# Generated by FakeRAM 2.0 (routing-friendly)
VERSION 5.7 ;
BUSBITCHARS "[]" ;
PROPERTYDEFINITIONS
  MACRO width INTEGER ;
  MACRO depth INTEGER ;
  MACRO banks INTEGER ;
END PROPERTYDEFINITIONS
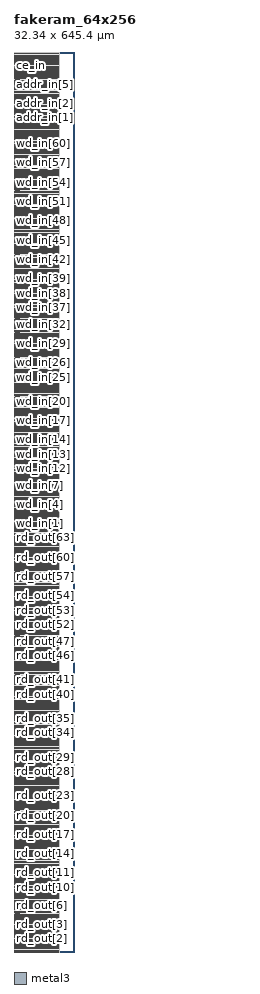
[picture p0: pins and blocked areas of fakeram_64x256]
MACRO fakeram_64x256
  PROPERTY width 64 ;
  PROPERTY depth 256 ;
  PROPERTY banks 1 ;
  FOREIGN fakeram_64x256 0 0 ;
  SYMMETRY X Y R90 ;
  SIZE 32.340 BY 645.400 ;
  CLASS BLOCK ;
  PIN rd_out[0]
    DIRECTION OUTPUT ;
    USE SIGNAL ;
    PORT
      LAYER metal3 ;
      RECT 1.000 0.140 3.000 0.210 ;
    END
    PORT
      LAYER metal3 ;
      RECT 1.000 0.105 4.000 0.245 ;
    END
  END rd_out[0]
  PIN rd_out[1]
    DIRECTION OUTPUT ;
    USE SIGNAL ;
    PORT
      LAYER metal3 ;
      RECT 1.000 4.760 3.000 4.830 ;
    END
    PORT
      LAYER metal3 ;
      RECT 1.000 4.725 4.000 4.865 ;
    END
  END rd_out[1]
  PIN rd_out[2]
    DIRECTION OUTPUT ;
    USE SIGNAL ;
    PORT
      LAYER metal3 ;
      RECT 1.000 9.380 3.000 9.450 ;
    END
    PORT
      LAYER metal3 ;
      RECT 1.000 9.345 4.000 9.485 ;
    END
  END rd_out[2]
  PIN rd_out[3]
    DIRECTION OUTPUT ;
    USE SIGNAL ;
    PORT
      LAYER metal3 ;
      RECT 1.000 14.000 3.000 14.070 ;
    END
    PORT
      LAYER metal3 ;
      RECT 1.000 13.965 4.000 14.105 ;
    END
  END rd_out[3]
  PIN rd_out[4]
    DIRECTION OUTPUT ;
    USE SIGNAL ;
    PORT
      LAYER metal3 ;
      RECT 1.000 18.620 3.000 18.690 ;
    END
    PORT
      LAYER metal3 ;
      RECT 1.000 18.585 4.000 18.725 ;
    END
  END rd_out[4]
  PIN rd_out[5]
    DIRECTION OUTPUT ;
    USE SIGNAL ;
    PORT
      LAYER metal3 ;
      RECT 1.000 23.240 3.000 23.310 ;
    END
    PORT
      LAYER metal3 ;
      RECT 1.000 23.205 4.000 23.345 ;
    END
  END rd_out[5]
  PIN rd_out[6]
    DIRECTION OUTPUT ;
    USE SIGNAL ;
    PORT
      LAYER metal3 ;
      RECT 1.000 27.860 3.000 27.930 ;
    END
    PORT
      LAYER metal3 ;
      RECT 1.000 27.825 4.000 27.965 ;
    END
  END rd_out[6]
  PIN rd_out[7]
    DIRECTION OUTPUT ;
    USE SIGNAL ;
    PORT
      LAYER metal3 ;
      RECT 1.000 32.480 3.000 32.550 ;
    END
    PORT
      LAYER metal3 ;
      RECT 1.000 32.445 4.000 32.585 ;
    END
  END rd_out[7]
  PIN rd_out[8]
    DIRECTION OUTPUT ;
    USE SIGNAL ;
    PORT
      LAYER metal3 ;
      RECT 1.000 37.100 3.000 37.170 ;
    END
    PORT
      LAYER metal3 ;
      RECT 1.000 37.065 4.000 37.205 ;
    END
  END rd_out[8]
  PIN rd_out[9]
    DIRECTION OUTPUT ;
    USE SIGNAL ;
    PORT
      LAYER metal3 ;
      RECT 1.000 41.720 3.000 41.790 ;
    END
    PORT
      LAYER metal3 ;
      RECT 1.000 41.685 4.000 41.825 ;
    END
  END rd_out[9]
  PIN rd_out[10]
    DIRECTION OUTPUT ;
    USE SIGNAL ;
    PORT
      LAYER metal3 ;
      RECT 1.000 46.340 3.000 46.410 ;
    END
    PORT
      LAYER metal3 ;
      RECT 1.000 46.305 4.000 46.445 ;
    END
  END rd_out[10]
  PIN rd_out[11]
    DIRECTION OUTPUT ;
    USE SIGNAL ;
    PORT
      LAYER metal3 ;
      RECT 1.000 50.960 3.000 51.030 ;
    END
    PORT
      LAYER metal3 ;
      RECT 1.000 50.925 4.000 51.065 ;
    END
  END rd_out[11]
  PIN rd_out[12]
    DIRECTION OUTPUT ;
    USE SIGNAL ;
    PORT
      LAYER metal3 ;
      RECT 1.000 55.580 3.000 55.650 ;
    END
    PORT
      LAYER metal3 ;
      RECT 1.000 55.545 4.000 55.685 ;
    END
  END rd_out[12]
  PIN rd_out[13]
    DIRECTION OUTPUT ;
    USE SIGNAL ;
    PORT
      LAYER metal3 ;
      RECT 1.000 60.200 3.000 60.270 ;
    END
    PORT
      LAYER metal3 ;
      RECT 1.000 60.165 4.000 60.305 ;
    END
  END rd_out[13]
  PIN rd_out[14]
    DIRECTION OUTPUT ;
    USE SIGNAL ;
    PORT
      LAYER metal3 ;
      RECT 1.000 64.820 3.000 64.890 ;
    END
    PORT
      LAYER metal3 ;
      RECT 1.000 64.785 4.000 64.925 ;
    END
  END rd_out[14]
  PIN rd_out[15]
    DIRECTION OUTPUT ;
    USE SIGNAL ;
    PORT
      LAYER metal3 ;
      RECT 1.000 69.440 3.000 69.510 ;
    END
    PORT
      LAYER metal3 ;
      RECT 1.000 69.405 4.000 69.545 ;
    END
  END rd_out[15]
  PIN rd_out[16]
    DIRECTION OUTPUT ;
    USE SIGNAL ;
    PORT
      LAYER metal3 ;
      RECT 1.000 74.060 3.000 74.130 ;
    END
    PORT
      LAYER metal3 ;
      RECT 1.000 74.025 4.000 74.165 ;
    END
  END rd_out[16]
  PIN rd_out[17]
    DIRECTION OUTPUT ;
    USE SIGNAL ;
    PORT
      LAYER metal3 ;
      RECT 1.000 78.680 3.000 78.750 ;
    END
    PORT
      LAYER metal3 ;
      RECT 1.000 78.645 4.000 78.785 ;
    END
  END rd_out[17]
  PIN rd_out[18]
    DIRECTION OUTPUT ;
    USE SIGNAL ;
    PORT
      LAYER metal3 ;
      RECT 1.000 83.300 3.000 83.370 ;
    END
    PORT
      LAYER metal3 ;
      RECT 1.000 83.265 4.000 83.405 ;
    END
  END rd_out[18]
  PIN rd_out[19]
    DIRECTION OUTPUT ;
    USE SIGNAL ;
    PORT
      LAYER metal3 ;
      RECT 1.000 87.920 3.000 87.990 ;
    END
    PORT
      LAYER metal3 ;
      RECT 1.000 87.885 4.000 88.025 ;
    END
  END rd_out[19]
  PIN rd_out[20]
    DIRECTION OUTPUT ;
    USE SIGNAL ;
    PORT
      LAYER metal3 ;
      RECT 1.000 92.540 3.000 92.610 ;
    END
    PORT
      LAYER metal3 ;
      RECT 1.000 92.505 4.000 92.645 ;
    END
  END rd_out[20]
  PIN rd_out[21]
    DIRECTION OUTPUT ;
    USE SIGNAL ;
    PORT
      LAYER metal3 ;
      RECT 1.000 97.160 3.000 97.230 ;
    END
    PORT
      LAYER metal3 ;
      RECT 1.000 97.125 4.000 97.265 ;
    END
  END rd_out[21]
  PIN rd_out[22]
    DIRECTION OUTPUT ;
    USE SIGNAL ;
    PORT
      LAYER metal3 ;
      RECT 1.000 101.780 3.000 101.850 ;
    END
    PORT
      LAYER metal3 ;
      RECT 1.000 101.745 4.000 101.885 ;
    END
  END rd_out[22]
  PIN rd_out[23]
    DIRECTION OUTPUT ;
    USE SIGNAL ;
    PORT
      LAYER metal3 ;
      RECT 1.000 106.400 3.000 106.470 ;
    END
    PORT
      LAYER metal3 ;
      RECT 1.000 106.365 4.000 106.505 ;
    END
  END rd_out[23]
  PIN rd_out[24]
    DIRECTION OUTPUT ;
    USE SIGNAL ;
    PORT
      LAYER metal3 ;
      RECT 1.000 111.020 3.000 111.090 ;
    END
    PORT
      LAYER metal3 ;
      RECT 1.000 110.985 4.000 111.125 ;
    END
  END rd_out[24]
  PIN rd_out[25]
    DIRECTION OUTPUT ;
    USE SIGNAL ;
    PORT
      LAYER metal3 ;
      RECT 1.000 115.640 3.000 115.710 ;
    END
    PORT
      LAYER metal3 ;
      RECT 1.000 115.605 4.000 115.745 ;
    END
  END rd_out[25]
  PIN rd_out[26]
    DIRECTION OUTPUT ;
    USE SIGNAL ;
    PORT
      LAYER metal3 ;
      RECT 1.000 120.260 3.000 120.330 ;
    END
    PORT
      LAYER metal3 ;
      RECT 1.000 120.225 4.000 120.365 ;
    END
  END rd_out[26]
  PIN rd_out[27]
    DIRECTION OUTPUT ;
    USE SIGNAL ;
    PORT
      LAYER metal3 ;
      RECT 1.000 124.880 3.000 124.950 ;
    END
    PORT
      LAYER metal3 ;
      RECT 1.000 124.845 4.000 124.985 ;
    END
  END rd_out[27]
  PIN rd_out[28]
    DIRECTION OUTPUT ;
    USE SIGNAL ;
    PORT
      LAYER metal3 ;
      RECT 1.000 129.500 3.000 129.570 ;
    END
    PORT
      LAYER metal3 ;
      RECT 1.000 129.465 4.000 129.605 ;
    END
  END rd_out[28]
  PIN rd_out[29]
    DIRECTION OUTPUT ;
    USE SIGNAL ;
    PORT
      LAYER metal3 ;
      RECT 1.000 134.120 3.000 134.190 ;
    END
    PORT
      LAYER metal3 ;
      RECT 1.000 134.085 4.000 134.225 ;
    END
  END rd_out[29]
  PIN rd_out[30]
    DIRECTION OUTPUT ;
    USE SIGNAL ;
    PORT
      LAYER metal3 ;
      RECT 1.000 138.740 3.000 138.810 ;
    END
    PORT
      LAYER metal3 ;
      RECT 1.000 138.705 4.000 138.845 ;
    END
  END rd_out[30]
  PIN rd_out[31]
    DIRECTION OUTPUT ;
    USE SIGNAL ;
    PORT
      LAYER metal3 ;
      RECT 1.000 143.360 3.000 143.430 ;
    END
    PORT
      LAYER metal3 ;
      RECT 1.000 143.325 4.000 143.465 ;
    END
  END rd_out[31]
  PIN rd_out[32]
    DIRECTION OUTPUT ;
    USE SIGNAL ;
    PORT
      LAYER metal3 ;
      RECT 1.000 147.980 3.000 148.050 ;
    END
    PORT
      LAYER metal3 ;
      RECT 1.000 147.945 4.000 148.085 ;
    END
  END rd_out[32]
  PIN rd_out[33]
    DIRECTION OUTPUT ;
    USE SIGNAL ;
    PORT
      LAYER metal3 ;
      RECT 1.000 152.600 3.000 152.670 ;
    END
    PORT
      LAYER metal3 ;
      RECT 1.000 152.565 4.000 152.705 ;
    END
  END rd_out[33]
  PIN rd_out[34]
    DIRECTION OUTPUT ;
    USE SIGNAL ;
    PORT
      LAYER metal3 ;
      RECT 1.000 157.220 3.000 157.290 ;
    END
    PORT
      LAYER metal3 ;
      RECT 1.000 157.185 4.000 157.325 ;
    END
  END rd_out[34]
  PIN rd_out[35]
    DIRECTION OUTPUT ;
    USE SIGNAL ;
    PORT
      LAYER metal3 ;
      RECT 1.000 161.840 3.000 161.910 ;
    END
    PORT
      LAYER metal3 ;
      RECT 1.000 161.805 4.000 161.945 ;
    END
  END rd_out[35]
  PIN rd_out[36]
    DIRECTION OUTPUT ;
    USE SIGNAL ;
    PORT
      LAYER metal3 ;
      RECT 1.000 166.460 3.000 166.530 ;
    END
    PORT
      LAYER metal3 ;
      RECT 1.000 166.425 4.000 166.565 ;
    END
  END rd_out[36]
  PIN rd_out[37]
    DIRECTION OUTPUT ;
    USE SIGNAL ;
    PORT
      LAYER metal3 ;
      RECT 1.000 171.080 3.000 171.150 ;
    END
    PORT
      LAYER metal3 ;
      RECT 1.000 171.045 4.000 171.185 ;
    END
  END rd_out[37]
  PIN rd_out[38]
    DIRECTION OUTPUT ;
    USE SIGNAL ;
    PORT
      LAYER metal3 ;
      RECT 1.000 175.700 3.000 175.770 ;
    END
    PORT
      LAYER metal3 ;
      RECT 1.000 175.665 4.000 175.805 ;
    END
  END rd_out[38]
  PIN rd_out[39]
    DIRECTION OUTPUT ;
    USE SIGNAL ;
    PORT
      LAYER metal3 ;
      RECT 1.000 180.320 3.000 180.390 ;
    END
    PORT
      LAYER metal3 ;
      RECT 1.000 180.285 4.000 180.425 ;
    END
  END rd_out[39]
  PIN rd_out[40]
    DIRECTION OUTPUT ;
    USE SIGNAL ;
    PORT
      LAYER metal3 ;
      RECT 1.000 184.940 3.000 185.010 ;
    END
    PORT
      LAYER metal3 ;
      RECT 1.000 184.905 4.000 185.045 ;
    END
  END rd_out[40]
  PIN rd_out[41]
    DIRECTION OUTPUT ;
    USE SIGNAL ;
    PORT
      LAYER metal3 ;
      RECT 1.000 189.560 3.000 189.630 ;
    END
    PORT
      LAYER metal3 ;
      RECT 1.000 189.525 4.000 189.665 ;
    END
  END rd_out[41]
  PIN rd_out[42]
    DIRECTION OUTPUT ;
    USE SIGNAL ;
    PORT
      LAYER metal3 ;
      RECT 1.000 194.180 3.000 194.250 ;
    END
    PORT
      LAYER metal3 ;
      RECT 1.000 194.145 4.000 194.285 ;
    END
  END rd_out[42]
  PIN rd_out[43]
    DIRECTION OUTPUT ;
    USE SIGNAL ;
    PORT
      LAYER metal3 ;
      RECT 1.000 198.800 3.000 198.870 ;
    END
    PORT
      LAYER metal3 ;
      RECT 1.000 198.765 4.000 198.905 ;
    END
  END rd_out[43]
  PIN rd_out[44]
    DIRECTION OUTPUT ;
    USE SIGNAL ;
    PORT
      LAYER metal3 ;
      RECT 1.000 203.420 3.000 203.490 ;
    END
    PORT
      LAYER metal3 ;
      RECT 1.000 203.385 4.000 203.525 ;
    END
  END rd_out[44]
  PIN rd_out[45]
    DIRECTION OUTPUT ;
    USE SIGNAL ;
    PORT
      LAYER metal3 ;
      RECT 1.000 208.040 3.000 208.110 ;
    END
    PORT
      LAYER metal3 ;
      RECT 1.000 208.005 4.000 208.145 ;
    END
  END rd_out[45]
  PIN rd_out[46]
    DIRECTION OUTPUT ;
    USE SIGNAL ;
    PORT
      LAYER metal3 ;
      RECT 1.000 212.660 3.000 212.730 ;
    END
    PORT
      LAYER metal3 ;
      RECT 1.000 212.625 4.000 212.765 ;
    END
  END rd_out[46]
  PIN rd_out[47]
    DIRECTION OUTPUT ;
    USE SIGNAL ;
    PORT
      LAYER metal3 ;
      RECT 1.000 217.280 3.000 217.350 ;
    END
    PORT
      LAYER metal3 ;
      RECT 1.000 217.245 4.000 217.385 ;
    END
  END rd_out[47]
  PIN rd_out[48]
    DIRECTION OUTPUT ;
    USE SIGNAL ;
    PORT
      LAYER metal3 ;
      RECT 1.000 221.900 3.000 221.970 ;
    END
    PORT
      LAYER metal3 ;
      RECT 1.000 221.865 4.000 222.005 ;
    END
  END rd_out[48]
  PIN rd_out[49]
    DIRECTION OUTPUT ;
    USE SIGNAL ;
    PORT
      LAYER metal3 ;
      RECT 1.000 226.520 3.000 226.590 ;
    END
    PORT
      LAYER metal3 ;
      RECT 1.000 226.485 4.000 226.625 ;
    END
  END rd_out[49]
  PIN rd_out[50]
    DIRECTION OUTPUT ;
    USE SIGNAL ;
    PORT
      LAYER metal3 ;
      RECT 1.000 231.140 3.000 231.210 ;
    END
    PORT
      LAYER metal3 ;
      RECT 1.000 231.105 4.000 231.245 ;
    END
  END rd_out[50]
  PIN rd_out[51]
    DIRECTION OUTPUT ;
    USE SIGNAL ;
    PORT
      LAYER metal3 ;
      RECT 1.000 235.760 3.000 235.830 ;
    END
    PORT
      LAYER metal3 ;
      RECT 1.000 235.725 4.000 235.865 ;
    END
  END rd_out[51]
  PIN rd_out[52]
    DIRECTION OUTPUT ;
    USE SIGNAL ;
    PORT
      LAYER metal3 ;
      RECT 1.000 240.380 3.000 240.450 ;
    END
    PORT
      LAYER metal3 ;
      RECT 1.000 240.345 4.000 240.485 ;
    END
  END rd_out[52]
  PIN rd_out[53]
    DIRECTION OUTPUT ;
    USE SIGNAL ;
    PORT
      LAYER metal3 ;
      RECT 1.000 245.000 3.000 245.070 ;
    END
    PORT
      LAYER metal3 ;
      RECT 1.000 244.965 4.000 245.105 ;
    END
  END rd_out[53]
  PIN rd_out[54]
    DIRECTION OUTPUT ;
    USE SIGNAL ;
    PORT
      LAYER metal3 ;
      RECT 1.000 249.620 3.000 249.690 ;
    END
    PORT
      LAYER metal3 ;
      RECT 1.000 249.585 4.000 249.725 ;
    END
  END rd_out[54]
  PIN rd_out[55]
    DIRECTION OUTPUT ;
    USE SIGNAL ;
    PORT
      LAYER metal3 ;
      RECT 1.000 254.240 3.000 254.310 ;
    END
    PORT
      LAYER metal3 ;
      RECT 1.000 254.205 4.000 254.345 ;
    END
  END rd_out[55]
  PIN rd_out[56]
    DIRECTION OUTPUT ;
    USE SIGNAL ;
    PORT
      LAYER metal3 ;
      RECT 1.000 258.860 3.000 258.930 ;
    END
    PORT
      LAYER metal3 ;
      RECT 1.000 258.825 4.000 258.965 ;
    END
  END rd_out[56]
  PIN rd_out[57]
    DIRECTION OUTPUT ;
    USE SIGNAL ;
    PORT
      LAYER metal3 ;
      RECT 1.000 263.480 3.000 263.550 ;
    END
    PORT
      LAYER metal3 ;
      RECT 1.000 263.445 4.000 263.585 ;
    END
  END rd_out[57]
  PIN rd_out[58]
    DIRECTION OUTPUT ;
    USE SIGNAL ;
    PORT
      LAYER metal3 ;
      RECT 1.000 268.100 3.000 268.170 ;
    END
    PORT
      LAYER metal3 ;
      RECT 1.000 268.065 4.000 268.205 ;
    END
  END rd_out[58]
  PIN rd_out[59]
    DIRECTION OUTPUT ;
    USE SIGNAL ;
    PORT
      LAYER metal3 ;
      RECT 1.000 272.720 3.000 272.790 ;
    END
    PORT
      LAYER metal3 ;
      RECT 1.000 272.685 4.000 272.825 ;
    END
  END rd_out[59]
  PIN rd_out[60]
    DIRECTION OUTPUT ;
    USE SIGNAL ;
    PORT
      LAYER metal3 ;
      RECT 1.000 277.340 3.000 277.410 ;
    END
    PORT
      LAYER metal3 ;
      RECT 1.000 277.305 4.000 277.445 ;
    END
  END rd_out[60]
  PIN rd_out[61]
    DIRECTION OUTPUT ;
    USE SIGNAL ;
    PORT
      LAYER metal3 ;
      RECT 1.000 281.960 3.000 282.030 ;
    END
    PORT
      LAYER metal3 ;
      RECT 1.000 281.925 4.000 282.065 ;
    END
  END rd_out[61]
  PIN rd_out[62]
    DIRECTION OUTPUT ;
    USE SIGNAL ;
    PORT
      LAYER metal3 ;
      RECT 1.000 286.580 3.000 286.650 ;
    END
    PORT
      LAYER metal3 ;
      RECT 1.000 286.545 4.000 286.685 ;
    END
  END rd_out[62]
  PIN rd_out[63]
    DIRECTION OUTPUT ;
    USE SIGNAL ;
    PORT
      LAYER metal3 ;
      RECT 1.000 291.200 3.000 291.270 ;
    END
    PORT
      LAYER metal3 ;
      RECT 1.000 291.165 4.000 291.305 ;
    END
  END rd_out[63]
  PIN wd_in[0]
    DIRECTION INPUT ;
    USE SIGNAL ;
    PORT
      LAYER metal3 ;
      RECT 1.000 296.800 3.000 296.870 ;
    END
    PORT
      LAYER metal3 ;
      RECT 1.000 296.765 4.000 296.905 ;
    END
  END wd_in[0]
  PIN wd_in[1]
    DIRECTION INPUT ;
    USE SIGNAL ;
    PORT
      LAYER metal3 ;
      RECT 1.000 301.420 3.000 301.490 ;
    END
    PORT
      LAYER metal3 ;
      RECT 1.000 301.385 4.000 301.525 ;
    END
  END wd_in[1]
  PIN wd_in[2]
    DIRECTION INPUT ;
    USE SIGNAL ;
    PORT
      LAYER metal3 ;
      RECT 1.000 306.040 3.000 306.110 ;
    END
    PORT
      LAYER metal3 ;
      RECT 1.000 306.005 4.000 306.145 ;
    END
  END wd_in[2]
  PIN wd_in[3]
    DIRECTION INPUT ;
    USE SIGNAL ;
    PORT
      LAYER metal3 ;
      RECT 1.000 310.660 3.000 310.730 ;
    END
    PORT
      LAYER metal3 ;
      RECT 1.000 310.625 4.000 310.765 ;
    END
  END wd_in[3]
  PIN wd_in[4]
    DIRECTION INPUT ;
    USE SIGNAL ;
    PORT
      LAYER metal3 ;
      RECT 1.000 315.280 3.000 315.350 ;
    END
    PORT
      LAYER metal3 ;
      RECT 1.000 315.245 4.000 315.385 ;
    END
  END wd_in[4]
  PIN wd_in[5]
    DIRECTION INPUT ;
    USE SIGNAL ;
    PORT
      LAYER metal3 ;
      RECT 1.000 319.900 3.000 319.970 ;
    END
    PORT
      LAYER metal3 ;
      RECT 1.000 319.865 4.000 320.005 ;
    END
  END wd_in[5]
  PIN wd_in[6]
    DIRECTION INPUT ;
    USE SIGNAL ;
    PORT
      LAYER metal3 ;
      RECT 1.000 324.520 3.000 324.590 ;
    END
    PORT
      LAYER metal3 ;
      RECT 1.000 324.485 4.000 324.625 ;
    END
  END wd_in[6]
  PIN wd_in[7]
    DIRECTION INPUT ;
    USE SIGNAL ;
    PORT
      LAYER metal3 ;
      RECT 1.000 329.140 3.000 329.210 ;
    END
    PORT
      LAYER metal3 ;
      RECT 1.000 329.105 4.000 329.245 ;
    END
  END wd_in[7]
  PIN wd_in[8]
    DIRECTION INPUT ;
    USE SIGNAL ;
    PORT
      LAYER metal3 ;
      RECT 1.000 333.760 3.000 333.830 ;
    END
    PORT
      LAYER metal3 ;
      RECT 1.000 333.725 4.000 333.865 ;
    END
  END wd_in[8]
  PIN wd_in[9]
    DIRECTION INPUT ;
    USE SIGNAL ;
    PORT
      LAYER metal3 ;
      RECT 1.000 338.380 3.000 338.450 ;
    END
    PORT
      LAYER metal3 ;
      RECT 1.000 338.345 4.000 338.485 ;
    END
  END wd_in[9]
  PIN wd_in[10]
    DIRECTION INPUT ;
    USE SIGNAL ;
    PORT
      LAYER metal3 ;
      RECT 1.000 343.000 3.000 343.070 ;
    END
    PORT
      LAYER metal3 ;
      RECT 1.000 342.965 4.000 343.105 ;
    END
  END wd_in[10]
  PIN wd_in[11]
    DIRECTION INPUT ;
    USE SIGNAL ;
    PORT
      LAYER metal3 ;
      RECT 1.000 347.620 3.000 347.690 ;
    END
    PORT
      LAYER metal3 ;
      RECT 1.000 347.585 4.000 347.725 ;
    END
  END wd_in[11]
  PIN wd_in[12]
    DIRECTION INPUT ;
    USE SIGNAL ;
    PORT
      LAYER metal3 ;
      RECT 1.000 352.240 3.000 352.310 ;
    END
    PORT
      LAYER metal3 ;
      RECT 1.000 352.205 4.000 352.345 ;
    END
  END wd_in[12]
  PIN wd_in[13]
    DIRECTION INPUT ;
    USE SIGNAL ;
    PORT
      LAYER metal3 ;
      RECT 1.000 356.860 3.000 356.930 ;
    END
    PORT
      LAYER metal3 ;
      RECT 1.000 356.825 4.000 356.965 ;
    END
  END wd_in[13]
  PIN wd_in[14]
    DIRECTION INPUT ;
    USE SIGNAL ;
    PORT
      LAYER metal3 ;
      RECT 1.000 361.480 3.000 361.550 ;
    END
    PORT
      LAYER metal3 ;
      RECT 1.000 361.445 4.000 361.585 ;
    END
  END wd_in[14]
  PIN wd_in[15]
    DIRECTION INPUT ;
    USE SIGNAL ;
    PORT
      LAYER metal3 ;
      RECT 1.000 366.100 3.000 366.170 ;
    END
    PORT
      LAYER metal3 ;
      RECT 1.000 366.065 4.000 366.205 ;
    END
  END wd_in[15]
  PIN wd_in[16]
    DIRECTION INPUT ;
    USE SIGNAL ;
    PORT
      LAYER metal3 ;
      RECT 1.000 370.720 3.000 370.790 ;
    END
    PORT
      LAYER metal3 ;
      RECT 1.000 370.685 4.000 370.825 ;
    END
  END wd_in[16]
  PIN wd_in[17]
    DIRECTION INPUT ;
    USE SIGNAL ;
    PORT
      LAYER metal3 ;
      RECT 1.000 375.340 3.000 375.410 ;
    END
    PORT
      LAYER metal3 ;
      RECT 1.000 375.305 4.000 375.445 ;
    END
  END wd_in[17]
  PIN wd_in[18]
    DIRECTION INPUT ;
    USE SIGNAL ;
    PORT
      LAYER metal3 ;
      RECT 1.000 379.960 3.000 380.030 ;
    END
    PORT
      LAYER metal3 ;
      RECT 1.000 379.925 4.000 380.065 ;
    END
  END wd_in[18]
  PIN wd_in[19]
    DIRECTION INPUT ;
    USE SIGNAL ;
    PORT
      LAYER metal3 ;
      RECT 1.000 384.580 3.000 384.650 ;
    END
    PORT
      LAYER metal3 ;
      RECT 1.000 384.545 4.000 384.685 ;
    END
  END wd_in[19]
  PIN wd_in[20]
    DIRECTION INPUT ;
    USE SIGNAL ;
    PORT
      LAYER metal3 ;
      RECT 1.000 389.200 3.000 389.270 ;
    END
    PORT
      LAYER metal3 ;
      RECT 1.000 389.165 4.000 389.305 ;
    END
  END wd_in[20]
  PIN wd_in[21]
    DIRECTION INPUT ;
    USE SIGNAL ;
    PORT
      LAYER metal3 ;
      RECT 1.000 393.820 3.000 393.890 ;
    END
    PORT
      LAYER metal3 ;
      RECT 1.000 393.785 4.000 393.925 ;
    END
  END wd_in[21]
  PIN wd_in[22]
    DIRECTION INPUT ;
    USE SIGNAL ;
    PORT
      LAYER metal3 ;
      RECT 1.000 398.440 3.000 398.510 ;
    END
    PORT
      LAYER metal3 ;
      RECT 1.000 398.405 4.000 398.545 ;
    END
  END wd_in[22]
  PIN wd_in[23]
    DIRECTION INPUT ;
    USE SIGNAL ;
    PORT
      LAYER metal3 ;
      RECT 1.000 403.060 3.000 403.130 ;
    END
    PORT
      LAYER metal3 ;
      RECT 1.000 403.025 4.000 403.165 ;
    END
  END wd_in[23]
  PIN wd_in[24]
    DIRECTION INPUT ;
    USE SIGNAL ;
    PORT
      LAYER metal3 ;
      RECT 1.000 407.680 3.000 407.750 ;
    END
    PORT
      LAYER metal3 ;
      RECT 1.000 407.645 4.000 407.785 ;
    END
  END wd_in[24]
  PIN wd_in[25]
    DIRECTION INPUT ;
    USE SIGNAL ;
    PORT
      LAYER metal3 ;
      RECT 1.000 412.300 3.000 412.370 ;
    END
    PORT
      LAYER metal3 ;
      RECT 1.000 412.265 4.000 412.405 ;
    END
  END wd_in[25]
  PIN wd_in[26]
    DIRECTION INPUT ;
    USE SIGNAL ;
    PORT
      LAYER metal3 ;
      RECT 1.000 416.920 3.000 416.990 ;
    END
    PORT
      LAYER metal3 ;
      RECT 1.000 416.885 4.000 417.025 ;
    END
  END wd_in[26]
  PIN wd_in[27]
    DIRECTION INPUT ;
    USE SIGNAL ;
    PORT
      LAYER metal3 ;
      RECT 1.000 421.540 3.000 421.610 ;
    END
    PORT
      LAYER metal3 ;
      RECT 1.000 421.505 4.000 421.645 ;
    END
  END wd_in[27]
  PIN wd_in[28]
    DIRECTION INPUT ;
    USE SIGNAL ;
    PORT
      LAYER metal3 ;
      RECT 1.000 426.160 3.000 426.230 ;
    END
    PORT
      LAYER metal3 ;
      RECT 1.000 426.125 4.000 426.265 ;
    END
  END wd_in[28]
  PIN wd_in[29]
    DIRECTION INPUT ;
    USE SIGNAL ;
    PORT
      LAYER metal3 ;
      RECT 1.000 430.780 3.000 430.850 ;
    END
    PORT
      LAYER metal3 ;
      RECT 1.000 430.745 4.000 430.885 ;
    END
  END wd_in[29]
  PIN wd_in[30]
    DIRECTION INPUT ;
    USE SIGNAL ;
    PORT
      LAYER metal3 ;
      RECT 1.000 435.400 3.000 435.470 ;
    END
    PORT
      LAYER metal3 ;
      RECT 1.000 435.365 4.000 435.505 ;
    END
  END wd_in[30]
  PIN wd_in[31]
    DIRECTION INPUT ;
    USE SIGNAL ;
    PORT
      LAYER metal3 ;
      RECT 1.000 440.020 3.000 440.090 ;
    END
    PORT
      LAYER metal3 ;
      RECT 1.000 439.985 4.000 440.125 ;
    END
  END wd_in[31]
  PIN wd_in[32]
    DIRECTION INPUT ;
    USE SIGNAL ;
    PORT
      LAYER metal3 ;
      RECT 1.000 444.640 3.000 444.710 ;
    END
    PORT
      LAYER metal3 ;
      RECT 1.000 444.605 4.000 444.745 ;
    END
  END wd_in[32]
  PIN wd_in[33]
    DIRECTION INPUT ;
    USE SIGNAL ;
    PORT
      LAYER metal3 ;
      RECT 1.000 449.260 3.000 449.330 ;
    END
    PORT
      LAYER metal3 ;
      RECT 1.000 449.225 4.000 449.365 ;
    END
  END wd_in[33]
  PIN wd_in[34]
    DIRECTION INPUT ;
    USE SIGNAL ;
    PORT
      LAYER metal3 ;
      RECT 1.000 453.880 3.000 453.950 ;
    END
    PORT
      LAYER metal3 ;
      RECT 1.000 453.845 4.000 453.985 ;
    END
  END wd_in[34]
  PIN wd_in[35]
    DIRECTION INPUT ;
    USE SIGNAL ;
    PORT
      LAYER metal3 ;
      RECT 1.000 458.500 3.000 458.570 ;
    END
    PORT
      LAYER metal3 ;
      RECT 1.000 458.465 4.000 458.605 ;
    END
  END wd_in[35]
  PIN wd_in[36]
    DIRECTION INPUT ;
    USE SIGNAL ;
    PORT
      LAYER metal3 ;
      RECT 1.000 463.120 3.000 463.190 ;
    END
    PORT
      LAYER metal3 ;
      RECT 1.000 463.085 4.000 463.225 ;
    END
  END wd_in[36]
  PIN wd_in[37]
    DIRECTION INPUT ;
    USE SIGNAL ;
    PORT
      LAYER metal3 ;
      RECT 1.000 467.740 3.000 467.810 ;
    END
    PORT
      LAYER metal3 ;
      RECT 1.000 467.705 4.000 467.845 ;
    END
  END wd_in[37]
  PIN wd_in[38]
    DIRECTION INPUT ;
    USE SIGNAL ;
    PORT
      LAYER metal3 ;
      RECT 1.000 472.360 3.000 472.430 ;
    END
    PORT
      LAYER metal3 ;
      RECT 1.000 472.325 4.000 472.465 ;
    END
  END wd_in[38]
  PIN wd_in[39]
    DIRECTION INPUT ;
    USE SIGNAL ;
    PORT
      LAYER metal3 ;
      RECT 1.000 476.980 3.000 477.050 ;
    END
    PORT
      LAYER metal3 ;
      RECT 1.000 476.945 4.000 477.085 ;
    END
  END wd_in[39]
  PIN wd_in[40]
    DIRECTION INPUT ;
    USE SIGNAL ;
    PORT
      LAYER metal3 ;
      RECT 1.000 481.600 3.000 481.670 ;
    END
    PORT
      LAYER metal3 ;
      RECT 1.000 481.565 4.000 481.705 ;
    END
  END wd_in[40]
  PIN wd_in[41]
    DIRECTION INPUT ;
    USE SIGNAL ;
    PORT
      LAYER metal3 ;
      RECT 1.000 486.220 3.000 486.290 ;
    END
    PORT
      LAYER metal3 ;
      RECT 1.000 486.185 4.000 486.325 ;
    END
  END wd_in[41]
  PIN wd_in[42]
    DIRECTION INPUT ;
    USE SIGNAL ;
    PORT
      LAYER metal3 ;
      RECT 1.000 490.840 3.000 490.910 ;
    END
    PORT
      LAYER metal3 ;
      RECT 1.000 490.805 4.000 490.945 ;
    END
  END wd_in[42]
  PIN wd_in[43]
    DIRECTION INPUT ;
    USE SIGNAL ;
    PORT
      LAYER metal3 ;
      RECT 1.000 495.460 3.000 495.530 ;
    END
    PORT
      LAYER metal3 ;
      RECT 1.000 495.425 4.000 495.565 ;
    END
  END wd_in[43]
  PIN wd_in[44]
    DIRECTION INPUT ;
    USE SIGNAL ;
    PORT
      LAYER metal3 ;
      RECT 1.000 500.080 3.000 500.150 ;
    END
    PORT
      LAYER metal3 ;
      RECT 1.000 500.045 4.000 500.185 ;
    END
  END wd_in[44]
  PIN wd_in[45]
    DIRECTION INPUT ;
    USE SIGNAL ;
    PORT
      LAYER metal3 ;
      RECT 1.000 504.700 3.000 504.770 ;
    END
    PORT
      LAYER metal3 ;
      RECT 1.000 504.665 4.000 504.805 ;
    END
  END wd_in[45]
  PIN wd_in[46]
    DIRECTION INPUT ;
    USE SIGNAL ;
    PORT
      LAYER metal3 ;
      RECT 1.000 509.320 3.000 509.390 ;
    END
    PORT
      LAYER metal3 ;
      RECT 1.000 509.285 4.000 509.425 ;
    END
  END wd_in[46]
  PIN wd_in[47]
    DIRECTION INPUT ;
    USE SIGNAL ;
    PORT
      LAYER metal3 ;
      RECT 1.000 513.940 3.000 514.010 ;
    END
    PORT
      LAYER metal3 ;
      RECT 1.000 513.905 4.000 514.045 ;
    END
  END wd_in[47]
  PIN wd_in[48]
    DIRECTION INPUT ;
    USE SIGNAL ;
    PORT
      LAYER metal3 ;
      RECT 1.000 518.560 3.000 518.630 ;
    END
    PORT
      LAYER metal3 ;
      RECT 1.000 518.525 4.000 518.665 ;
    END
  END wd_in[48]
  PIN wd_in[49]
    DIRECTION INPUT ;
    USE SIGNAL ;
    PORT
      LAYER metal3 ;
      RECT 1.000 523.180 3.000 523.250 ;
    END
    PORT
      LAYER metal3 ;
      RECT 1.000 523.145 4.000 523.285 ;
    END
  END wd_in[49]
  PIN wd_in[50]
    DIRECTION INPUT ;
    USE SIGNAL ;
    PORT
      LAYER metal3 ;
      RECT 1.000 527.800 3.000 527.870 ;
    END
    PORT
      LAYER metal3 ;
      RECT 1.000 527.765 4.000 527.905 ;
    END
  END wd_in[50]
  PIN wd_in[51]
    DIRECTION INPUT ;
    USE SIGNAL ;
    PORT
      LAYER metal3 ;
      RECT 1.000 532.420 3.000 532.490 ;
    END
    PORT
      LAYER metal3 ;
      RECT 1.000 532.385 4.000 532.525 ;
    END
  END wd_in[51]
  PIN wd_in[52]
    DIRECTION INPUT ;
    USE SIGNAL ;
    PORT
      LAYER metal3 ;
      RECT 1.000 537.040 3.000 537.110 ;
    END
    PORT
      LAYER metal3 ;
      RECT 1.000 537.005 4.000 537.145 ;
    END
  END wd_in[52]
  PIN wd_in[53]
    DIRECTION INPUT ;
    USE SIGNAL ;
    PORT
      LAYER metal3 ;
      RECT 1.000 541.660 3.000 541.730 ;
    END
    PORT
      LAYER metal3 ;
      RECT 1.000 541.625 4.000 541.765 ;
    END
  END wd_in[53]
  PIN wd_in[54]
    DIRECTION INPUT ;
    USE SIGNAL ;
    PORT
      LAYER metal3 ;
      RECT 1.000 546.280 3.000 546.350 ;
    END
    PORT
      LAYER metal3 ;
      RECT 1.000 546.245 4.000 546.385 ;
    END
  END wd_in[54]
  PIN wd_in[55]
    DIRECTION INPUT ;
    USE SIGNAL ;
    PORT
      LAYER metal3 ;
      RECT 1.000 550.900 3.000 550.970 ;
    END
    PORT
      LAYER metal3 ;
      RECT 1.000 550.865 4.000 551.005 ;
    END
  END wd_in[55]
  PIN wd_in[56]
    DIRECTION INPUT ;
    USE SIGNAL ;
    PORT
      LAYER metal3 ;
      RECT 1.000 555.520 3.000 555.590 ;
    END
    PORT
      LAYER metal3 ;
      RECT 1.000 555.485 4.000 555.625 ;
    END
  END wd_in[56]
  PIN wd_in[57]
    DIRECTION INPUT ;
    USE SIGNAL ;
    PORT
      LAYER metal3 ;
      RECT 1.000 560.140 3.000 560.210 ;
    END
    PORT
      LAYER metal3 ;
      RECT 1.000 560.105 4.000 560.245 ;
    END
  END wd_in[57]
  PIN wd_in[58]
    DIRECTION INPUT ;
    USE SIGNAL ;
    PORT
      LAYER metal3 ;
      RECT 1.000 564.760 3.000 564.830 ;
    END
    PORT
      LAYER metal3 ;
      RECT 1.000 564.725 4.000 564.865 ;
    END
  END wd_in[58]
  PIN wd_in[59]
    DIRECTION INPUT ;
    USE SIGNAL ;
    PORT
      LAYER metal3 ;
      RECT 1.000 569.380 3.000 569.450 ;
    END
    PORT
      LAYER metal3 ;
      RECT 1.000 569.345 4.000 569.485 ;
    END
  END wd_in[59]
  PIN wd_in[60]
    DIRECTION INPUT ;
    USE SIGNAL ;
    PORT
      LAYER metal3 ;
      RECT 1.000 574.000 3.000 574.070 ;
    END
    PORT
      LAYER metal3 ;
      RECT 1.000 573.965 4.000 574.105 ;
    END
  END wd_in[60]
  PIN wd_in[61]
    DIRECTION INPUT ;
    USE SIGNAL ;
    PORT
      LAYER metal3 ;
      RECT 1.000 578.620 3.000 578.690 ;
    END
    PORT
      LAYER metal3 ;
      RECT 1.000 578.585 4.000 578.725 ;
    END
  END wd_in[61]
  PIN wd_in[62]
    DIRECTION INPUT ;
    USE SIGNAL ;
    PORT
      LAYER metal3 ;
      RECT 1.000 583.240 3.000 583.310 ;
    END
    PORT
      LAYER metal3 ;
      RECT 1.000 583.205 4.000 583.345 ;
    END
  END wd_in[62]
  PIN wd_in[63]
    DIRECTION INPUT ;
    USE SIGNAL ;
    PORT
      LAYER metal3 ;
      RECT 1.000 587.860 3.000 587.930 ;
    END
    PORT
      LAYER metal3 ;
      RECT 1.000 587.825 4.000 587.965 ;
    END
  END wd_in[63]
  PIN addr_in[0]
    DIRECTION INPUT ;
    USE SIGNAL ;
    PORT
      LAYER metal3 ;
      RECT 1.000 593.460 3.000 593.530 ;
    END
    PORT
      LAYER metal3 ;
      RECT 1.000 593.425 4.000 593.565 ;
    END
  END addr_in[0]
  PIN addr_in[1]
    DIRECTION INPUT ;
    USE SIGNAL ;
    PORT
      LAYER metal3 ;
      RECT 1.000 598.080 3.000 598.150 ;
    END
    PORT
      LAYER metal3 ;
      RECT 1.000 598.045 4.000 598.185 ;
    END
  END addr_in[1]
  PIN addr_in[2]
    DIRECTION INPUT ;
    USE SIGNAL ;
    PORT
      LAYER metal3 ;
      RECT 1.000 602.700 3.000 602.770 ;
    END
    PORT
      LAYER metal3 ;
      RECT 1.000 602.665 4.000 602.805 ;
    END
  END addr_in[2]
  PIN addr_in[3]
    DIRECTION INPUT ;
    USE SIGNAL ;
    PORT
      LAYER metal3 ;
      RECT 1.000 607.320 3.000 607.390 ;
    END
    PORT
      LAYER metal3 ;
      RECT 1.000 607.285 4.000 607.425 ;
    END
  END addr_in[3]
  PIN addr_in[4]
    DIRECTION INPUT ;
    USE SIGNAL ;
    PORT
      LAYER metal3 ;
      RECT 1.000 611.940 3.000 612.010 ;
    END
    PORT
      LAYER metal3 ;
      RECT 1.000 611.905 4.000 612.045 ;
    END
  END addr_in[4]
  PIN addr_in[5]
    DIRECTION INPUT ;
    USE SIGNAL ;
    PORT
      LAYER metal3 ;
      RECT 1.000 616.560 3.000 616.630 ;
    END
    PORT
      LAYER metal3 ;
      RECT 1.000 616.525 4.000 616.665 ;
    END
  END addr_in[5]
  PIN addr_in[6]
    DIRECTION INPUT ;
    USE SIGNAL ;
    PORT
      LAYER metal3 ;
      RECT 1.000 621.180 3.000 621.250 ;
    END
    PORT
      LAYER metal3 ;
      RECT 1.000 621.145 4.000 621.285 ;
    END
  END addr_in[6]
  PIN addr_in[7]
    DIRECTION INPUT ;
    USE SIGNAL ;
    PORT
      LAYER metal3 ;
      RECT 1.000 625.800 3.000 625.870 ;
    END
    PORT
      LAYER metal3 ;
      RECT 1.000 625.765 4.000 625.905 ;
    END
  END addr_in[7]
  PIN we_in
    DIRECTION INPUT ;
    USE SIGNAL ;
    PORT
      LAYER metal3 ;
      RECT 1.000 631.400 3.000 631.470 ;
    END
    PORT
      LAYER metal3 ;
      RECT 1.000 631.365 4.000 631.505 ;
    END
  END we_in
  PIN ce_in
    DIRECTION INPUT ;
    USE SIGNAL ;
    PORT
      LAYER metal3 ;
      RECT 1.000 636.020 3.000 636.090 ;
    END
    PORT
      LAYER metal3 ;
      RECT 1.000 635.985 4.000 636.125 ;
    END
  END ce_in
  PIN clk
    DIRECTION INPUT ;
    USE SIGNAL ;
    PORT
      LAYER metal3 ;
      RECT 1.000 640.640 3.000 640.710 ;
    END
    PORT
      LAYER metal3 ;
      RECT 1.000 640.605 4.000 640.745 ;
    END
  END clk
  PIN VSS
    DIRECTION INOUT ;
    USE GROUND ;
    PORT
      LAYER metal3 ;
      RECT 0.140 0.000 32.200 0.280 ;
      RECT 0.140 2.240 32.200 2.520 ;
      RECT 0.140 4.480 32.200 4.760 ;
      RECT 0.140 6.720 32.200 7.000 ;
      RECT 0.140 8.960 32.200 9.240 ;
      RECT 0.140 11.200 32.200 11.480 ;
      RECT 0.140 13.440 32.200 13.720 ;
      RECT 0.140 15.680 32.200 15.960 ;
      RECT 0.140 17.920 32.200 18.200 ;
      RECT 0.140 20.160 32.200 20.440 ;
      RECT 0.140 22.400 32.200 22.680 ;
      RECT 0.140 24.640 32.200 24.920 ;
      RECT 0.140 26.880 32.200 27.160 ;
      RECT 0.140 29.120 32.200 29.400 ;
      RECT 0.140 31.360 32.200 31.640 ;
      RECT 0.140 33.600 32.200 33.880 ;
      RECT 0.140 35.840 32.200 36.120 ;
      RECT 0.140 38.080 32.200 38.360 ;
      RECT 0.140 40.320 32.200 40.600 ;
      RECT 0.140 42.560 32.200 42.840 ;
      RECT 0.140 44.800 32.200 45.080 ;
      RECT 0.140 47.040 32.200 47.320 ;
      RECT 0.140 49.280 32.200 49.560 ;
      RECT 0.140 51.520 32.200 51.800 ;
      RECT 0.140 53.760 32.200 54.040 ;
      RECT 0.140 56.000 32.200 56.280 ;
      RECT 0.140 58.240 32.200 58.520 ;
      RECT 0.140 60.480 32.200 60.760 ;
      RECT 0.140 62.720 32.200 63.000 ;
      RECT 0.140 64.960 32.200 65.240 ;
      RECT 0.140 67.200 32.200 67.480 ;
      RECT 0.140 69.440 32.200 69.720 ;
      RECT 0.140 71.680 32.200 71.960 ;
      RECT 0.140 73.920 32.200 74.200 ;
      RECT 0.140 76.160 32.200 76.440 ;
      RECT 0.140 78.400 32.200 78.680 ;
      RECT 0.140 80.640 32.200 80.920 ;
      RECT 0.140 82.880 32.200 83.160 ;
      RECT 0.140 85.120 32.200 85.400 ;
      RECT 0.140 87.360 32.200 87.640 ;
      RECT 0.140 89.600 32.200 89.880 ;
      RECT 0.140 91.840 32.200 92.120 ;
      RECT 0.140 94.080 32.200 94.360 ;
      RECT 0.140 96.320 32.200 96.600 ;
      RECT 0.140 98.560 32.200 98.840 ;
      RECT 0.140 100.800 32.200 101.080 ;
      RECT 0.140 103.040 32.200 103.320 ;
      RECT 0.140 105.280 32.200 105.560 ;
      RECT 0.140 107.520 32.200 107.800 ;
      RECT 0.140 109.760 32.200 110.040 ;
      RECT 0.140 112.000 32.200 112.280 ;
      RECT 0.140 114.240 32.200 114.520 ;
      RECT 0.140 116.480 32.200 116.760 ;
      RECT 0.140 118.720 32.200 119.000 ;
      RECT 0.140 120.960 32.200 121.240 ;
      RECT 0.140 123.200 32.200 123.480 ;
      RECT 0.140 125.440 32.200 125.720 ;
      RECT 0.140 127.680 32.200 127.960 ;
      RECT 0.140 129.920 32.200 130.200 ;
      RECT 0.140 132.160 32.200 132.440 ;
      RECT 0.140 134.400 32.200 134.680 ;
      RECT 0.140 136.640 32.200 136.920 ;
      RECT 0.140 138.880 32.200 139.160 ;
      RECT 0.140 141.120 32.200 141.400 ;
      RECT 0.140 143.360 32.200 143.640 ;
      RECT 0.140 145.600 32.200 145.880 ;
      RECT 0.140 147.840 32.200 148.120 ;
      RECT 0.140 150.080 32.200 150.360 ;
      RECT 0.140 152.320 32.200 152.600 ;
      RECT 0.140 154.560 32.200 154.840 ;
      RECT 0.140 156.800 32.200 157.080 ;
      RECT 0.140 159.040 32.200 159.320 ;
      RECT 0.140 161.280 32.200 161.560 ;
      RECT 0.140 163.520 32.200 163.800 ;
      RECT 0.140 165.760 32.200 166.040 ;
      RECT 0.140 168.000 32.200 168.280 ;
      RECT 0.140 170.240 32.200 170.520 ;
      RECT 0.140 172.480 32.200 172.760 ;
      RECT 0.140 174.720 32.200 175.000 ;
      RECT 0.140 176.960 32.200 177.240 ;
      RECT 0.140 179.200 32.200 179.480 ;
      RECT 0.140 181.440 32.200 181.720 ;
      RECT 0.140 183.680 32.200 183.960 ;
      RECT 0.140 185.920 32.200 186.200 ;
      RECT 0.140 188.160 32.200 188.440 ;
      RECT 0.140 190.400 32.200 190.680 ;
      RECT 0.140 192.640 32.200 192.920 ;
      RECT 0.140 194.880 32.200 195.160 ;
      RECT 0.140 197.120 32.200 197.400 ;
      RECT 0.140 199.360 32.200 199.640 ;
      RECT 0.140 201.600 32.200 201.880 ;
      RECT 0.140 203.840 32.200 204.120 ;
      RECT 0.140 206.080 32.200 206.360 ;
      RECT 0.140 208.320 32.200 208.600 ;
      RECT 0.140 210.560 32.200 210.840 ;
      RECT 0.140 212.800 32.200 213.080 ;
      RECT 0.140 215.040 32.200 215.320 ;
      RECT 0.140 217.280 32.200 217.560 ;
      RECT 0.140 219.520 32.200 219.800 ;
      RECT 0.140 221.760 32.200 222.040 ;
      RECT 0.140 224.000 32.200 224.280 ;
      RECT 0.140 226.240 32.200 226.520 ;
      RECT 0.140 228.480 32.200 228.760 ;
      RECT 0.140 230.720 32.200 231.000 ;
      RECT 0.140 232.960 32.200 233.240 ;
      RECT 0.140 235.200 32.200 235.480 ;
      RECT 0.140 237.440 32.200 237.720 ;
      RECT 0.140 239.680 32.200 239.960 ;
      RECT 0.140 241.920 32.200 242.200 ;
      RECT 0.140 244.160 32.200 244.440 ;
      RECT 0.140 246.400 32.200 246.680 ;
      RECT 0.140 248.640 32.200 248.920 ;
      RECT 0.140 250.880 32.200 251.160 ;
      RECT 0.140 253.120 32.200 253.400 ;
      RECT 0.140 255.360 32.200 255.640 ;
      RECT 0.140 257.600 32.200 257.880 ;
      RECT 0.140 259.840 32.200 260.120 ;
      RECT 0.140 262.080 32.200 262.360 ;
      RECT 0.140 264.320 32.200 264.600 ;
      RECT 0.140 266.560 32.200 266.840 ;
      RECT 0.140 268.800 32.200 269.080 ;
      RECT 0.140 271.040 32.200 271.320 ;
      RECT 0.140 273.280 32.200 273.560 ;
      RECT 0.140 275.520 32.200 275.800 ;
      RECT 0.140 277.760 32.200 278.040 ;
      RECT 0.140 280.000 32.200 280.280 ;
      RECT 0.140 282.240 32.200 282.520 ;
      RECT 0.140 284.480 32.200 284.760 ;
      RECT 0.140 286.720 32.200 287.000 ;
      RECT 0.140 288.960 32.200 289.240 ;
      RECT 0.140 291.200 32.200 291.480 ;
      RECT 0.140 293.440 32.200 293.720 ;
      RECT 0.140 295.680 32.200 295.960 ;
      RECT 0.140 297.920 32.200 298.200 ;
      RECT 0.140 300.160 32.200 300.440 ;
      RECT 0.140 302.400 32.200 302.680 ;
      RECT 0.140 304.640 32.200 304.920 ;
      RECT 0.140 306.880 32.200 307.160 ;
      RECT 0.140 309.120 32.200 309.400 ;
      RECT 0.140 311.360 32.200 311.640 ;
      RECT 0.140 313.600 32.200 313.880 ;
      RECT 0.140 315.840 32.200 316.120 ;
      RECT 0.140 318.080 32.200 318.360 ;
      RECT 0.140 320.320 32.200 320.600 ;
      RECT 0.140 322.560 32.200 322.840 ;
      RECT 0.140 324.800 32.200 325.080 ;
      RECT 0.140 327.040 32.200 327.320 ;
      RECT 0.140 329.280 32.200 329.560 ;
      RECT 0.140 331.520 32.200 331.800 ;
      RECT 0.140 333.760 32.200 334.040 ;
      RECT 0.140 336.000 32.200 336.280 ;
      RECT 0.140 338.240 32.200 338.520 ;
      RECT 0.140 340.480 32.200 340.760 ;
      RECT 0.140 342.720 32.200 343.000 ;
      RECT 0.140 344.960 32.200 345.240 ;
      RECT 0.140 347.200 32.200 347.480 ;
      RECT 0.140 349.440 32.200 349.720 ;
      RECT 0.140 351.680 32.200 351.960 ;
      RECT 0.140 353.920 32.200 354.200 ;
      RECT 0.140 356.160 32.200 356.440 ;
      RECT 0.140 358.400 32.200 358.680 ;
      RECT 0.140 360.640 32.200 360.920 ;
      RECT 0.140 362.880 32.200 363.160 ;
      RECT 0.140 365.120 32.200 365.400 ;
      RECT 0.140 367.360 32.200 367.640 ;
      RECT 0.140 369.600 32.200 369.880 ;
      RECT 0.140 371.840 32.200 372.120 ;
      RECT 0.140 374.080 32.200 374.360 ;
      RECT 0.140 376.320 32.200 376.600 ;
      RECT 0.140 378.560 32.200 378.840 ;
      RECT 0.140 380.800 32.200 381.080 ;
      RECT 0.140 383.040 32.200 383.320 ;
      RECT 0.140 385.280 32.200 385.560 ;
      RECT 0.140 387.520 32.200 387.800 ;
      RECT 0.140 389.760 32.200 390.040 ;
      RECT 0.140 392.000 32.200 392.280 ;
      RECT 0.140 394.240 32.200 394.520 ;
      RECT 0.140 396.480 32.200 396.760 ;
      RECT 0.140 398.720 32.200 399.000 ;
      RECT 0.140 400.960 32.200 401.240 ;
      RECT 0.140 403.200 32.200 403.480 ;
      RECT 0.140 405.440 32.200 405.720 ;
      RECT 0.140 407.680 32.200 407.960 ;
      RECT 0.140 409.920 32.200 410.200 ;
      RECT 0.140 412.160 32.200 412.440 ;
      RECT 0.140 414.400 32.200 414.680 ;
      RECT 0.140 416.640 32.200 416.920 ;
      RECT 0.140 418.880 32.200 419.160 ;
      RECT 0.140 421.120 32.200 421.400 ;
      RECT 0.140 423.360 32.200 423.640 ;
      RECT 0.140 425.600 32.200 425.880 ;
      RECT 0.140 427.840 32.200 428.120 ;
      RECT 0.140 430.080 32.200 430.360 ;
      RECT 0.140 432.320 32.200 432.600 ;
      RECT 0.140 434.560 32.200 434.840 ;
      RECT 0.140 436.800 32.200 437.080 ;
      RECT 0.140 439.040 32.200 439.320 ;
      RECT 0.140 441.280 32.200 441.560 ;
      RECT 0.140 443.520 32.200 443.800 ;
      RECT 0.140 445.760 32.200 446.040 ;
      RECT 0.140 448.000 32.200 448.280 ;
      RECT 0.140 450.240 32.200 450.520 ;
      RECT 0.140 452.480 32.200 452.760 ;
      RECT 0.140 454.720 32.200 455.000 ;
      RECT 0.140 456.960 32.200 457.240 ;
      RECT 0.140 459.200 32.200 459.480 ;
      RECT 0.140 461.440 32.200 461.720 ;
      RECT 0.140 463.680 32.200 463.960 ;
      RECT 0.140 465.920 32.200 466.200 ;
      RECT 0.140 468.160 32.200 468.440 ;
      RECT 0.140 470.400 32.200 470.680 ;
      RECT 0.140 472.640 32.200 472.920 ;
      RECT 0.140 474.880 32.200 475.160 ;
      RECT 0.140 477.120 32.200 477.400 ;
      RECT 0.140 479.360 32.200 479.640 ;
      RECT 0.140 481.600 32.200 481.880 ;
      RECT 0.140 483.840 32.200 484.120 ;
      RECT 0.140 486.080 32.200 486.360 ;
      RECT 0.140 488.320 32.200 488.600 ;
      RECT 0.140 490.560 32.200 490.840 ;
      RECT 0.140 492.800 32.200 493.080 ;
      RECT 0.140 495.040 32.200 495.320 ;
      RECT 0.140 497.280 32.200 497.560 ;
      RECT 0.140 499.520 32.200 499.800 ;
      RECT 0.140 501.760 32.200 502.040 ;
      RECT 0.140 504.000 32.200 504.280 ;
      RECT 0.140 506.240 32.200 506.520 ;
      RECT 0.140 508.480 32.200 508.760 ;
      RECT 0.140 510.720 32.200 511.000 ;
      RECT 0.140 512.960 32.200 513.240 ;
      RECT 0.140 515.200 32.200 515.480 ;
      RECT 0.140 517.440 32.200 517.720 ;
      RECT 0.140 519.680 32.200 519.960 ;
      RECT 0.140 521.920 32.200 522.200 ;
      RECT 0.140 524.160 32.200 524.440 ;
      RECT 0.140 526.400 32.200 526.680 ;
      RECT 0.140 528.640 32.200 528.920 ;
      RECT 0.140 530.880 32.200 531.160 ;
      RECT 0.140 533.120 32.200 533.400 ;
      RECT 0.140 535.360 32.200 535.640 ;
      RECT 0.140 537.600 32.200 537.880 ;
      RECT 0.140 539.840 32.200 540.120 ;
      RECT 0.140 542.080 32.200 542.360 ;
      RECT 0.140 544.320 32.200 544.600 ;
      RECT 0.140 546.560 32.200 546.840 ;
      RECT 0.140 548.800 32.200 549.080 ;
      RECT 0.140 551.040 32.200 551.320 ;
      RECT 0.140 553.280 32.200 553.560 ;
      RECT 0.140 555.520 32.200 555.800 ;
      RECT 0.140 557.760 32.200 558.040 ;
      RECT 0.140 560.000 32.200 560.280 ;
      RECT 0.140 562.240 32.200 562.520 ;
      RECT 0.140 564.480 32.200 564.760 ;
      RECT 0.140 566.720 32.200 567.000 ;
      RECT 0.140 568.960 32.200 569.240 ;
      RECT 0.140 571.200 32.200 571.480 ;
      RECT 0.140 573.440 32.200 573.720 ;
      RECT 0.140 575.680 32.200 575.960 ;
      RECT 0.140 577.920 32.200 578.200 ;
      RECT 0.140 580.160 32.200 580.440 ;
      RECT 0.140 582.400 32.200 582.680 ;
      RECT 0.140 584.640 32.200 584.920 ;
      RECT 0.140 586.880 32.200 587.160 ;
      RECT 0.140 589.120 32.200 589.400 ;
      RECT 0.140 591.360 32.200 591.640 ;
      RECT 0.140 593.600 32.200 593.880 ;
      RECT 0.140 595.840 32.200 596.120 ;
      RECT 0.140 598.080 32.200 598.360 ;
      RECT 0.140 600.320 32.200 600.600 ;
      RECT 0.140 602.560 32.200 602.840 ;
      RECT 0.140 604.800 32.200 605.080 ;
      RECT 0.140 607.040 32.200 607.320 ;
      RECT 0.140 609.280 32.200 609.560 ;
      RECT 0.140 611.520 32.200 611.800 ;
      RECT 0.140 613.760 32.200 614.040 ;
      RECT 0.140 616.000 32.200 616.280 ;
      RECT 0.140 618.240 32.200 618.520 ;
      RECT 0.140 620.480 32.200 620.760 ;
      RECT 0.140 622.720 32.200 623.000 ;
      RECT 0.140 624.960 32.200 625.240 ;
      RECT 0.140 627.200 32.200 627.480 ;
      RECT 0.140 629.440 32.200 629.720 ;
      RECT 0.140 631.680 32.200 631.960 ;
      RECT 0.140 633.920 32.200 634.200 ;
      RECT 0.140 636.160 32.200 636.440 ;
      RECT 0.140 638.400 32.200 638.680 ;
      RECT 0.140 640.640 32.200 640.920 ;
      RECT 0.140 642.880 32.200 643.160 ;
    END
  END VSS
  PIN VDD
    DIRECTION INOUT ;
    USE POWER ;
    PORT
      LAYER metal3 ;
      RECT 0.140 1.120 32.200 1.400 ;
      RECT 0.140 3.360 32.200 3.640 ;
      RECT 0.140 5.600 32.200 5.880 ;
      RECT 0.140 7.840 32.200 8.120 ;
      RECT 0.140 10.080 32.200 10.360 ;
      RECT 0.140 12.320 32.200 12.600 ;
      RECT 0.140 14.560 32.200 14.840 ;
      RECT 0.140 16.800 32.200 17.080 ;
      RECT 0.140 19.040 32.200 19.320 ;
      RECT 0.140 21.280 32.200 21.560 ;
      RECT 0.140 23.520 32.200 23.800 ;
      RECT 0.140 25.760 32.200 26.040 ;
      RECT 0.140 28.000 32.200 28.280 ;
      RECT 0.140 30.240 32.200 30.520 ;
      RECT 0.140 32.480 32.200 32.760 ;
      RECT 0.140 34.720 32.200 35.000 ;
      RECT 0.140 36.960 32.200 37.240 ;
      RECT 0.140 39.200 32.200 39.480 ;
      RECT 0.140 41.440 32.200 41.720 ;
      RECT 0.140 43.680 32.200 43.960 ;
      RECT 0.140 45.920 32.200 46.200 ;
      RECT 0.140 48.160 32.200 48.440 ;
      RECT 0.140 50.400 32.200 50.680 ;
      RECT 0.140 52.640 32.200 52.920 ;
      RECT 0.140 54.880 32.200 55.160 ;
      RECT 0.140 57.120 32.200 57.400 ;
      RECT 0.140 59.360 32.200 59.640 ;
      RECT 0.140 61.600 32.200 61.880 ;
      RECT 0.140 63.840 32.200 64.120 ;
      RECT 0.140 66.080 32.200 66.360 ;
      RECT 0.140 68.320 32.200 68.600 ;
      RECT 0.140 70.560 32.200 70.840 ;
      RECT 0.140 72.800 32.200 73.080 ;
      RECT 0.140 75.040 32.200 75.320 ;
      RECT 0.140 77.280 32.200 77.560 ;
      RECT 0.140 79.520 32.200 79.800 ;
      RECT 0.140 81.760 32.200 82.040 ;
      RECT 0.140 84.000 32.200 84.280 ;
      RECT 0.140 86.240 32.200 86.520 ;
      RECT 0.140 88.480 32.200 88.760 ;
      RECT 0.140 90.720 32.200 91.000 ;
      RECT 0.140 92.960 32.200 93.240 ;
      RECT 0.140 95.200 32.200 95.480 ;
      RECT 0.140 97.440 32.200 97.720 ;
      RECT 0.140 99.680 32.200 99.960 ;
      RECT 0.140 101.920 32.200 102.200 ;
      RECT 0.140 104.160 32.200 104.440 ;
      RECT 0.140 106.400 32.200 106.680 ;
      RECT 0.140 108.640 32.200 108.920 ;
      RECT 0.140 110.880 32.200 111.160 ;
      RECT 0.140 113.120 32.200 113.400 ;
      RECT 0.140 115.360 32.200 115.640 ;
      RECT 0.140 117.600 32.200 117.880 ;
      RECT 0.140 119.840 32.200 120.120 ;
      RECT 0.140 122.080 32.200 122.360 ;
      RECT 0.140 124.320 32.200 124.600 ;
      RECT 0.140 126.560 32.200 126.840 ;
      RECT 0.140 128.800 32.200 129.080 ;
      RECT 0.140 131.040 32.200 131.320 ;
      RECT 0.140 133.280 32.200 133.560 ;
      RECT 0.140 135.520 32.200 135.800 ;
      RECT 0.140 137.760 32.200 138.040 ;
      RECT 0.140 140.000 32.200 140.280 ;
      RECT 0.140 142.240 32.200 142.520 ;
      RECT 0.140 144.480 32.200 144.760 ;
      RECT 0.140 146.720 32.200 147.000 ;
      RECT 0.140 148.960 32.200 149.240 ;
      RECT 0.140 151.200 32.200 151.480 ;
      RECT 0.140 153.440 32.200 153.720 ;
      RECT 0.140 155.680 32.200 155.960 ;
      RECT 0.140 157.920 32.200 158.200 ;
      RECT 0.140 160.160 32.200 160.440 ;
      RECT 0.140 162.400 32.200 162.680 ;
      RECT 0.140 164.640 32.200 164.920 ;
      RECT 0.140 166.880 32.200 167.160 ;
      RECT 0.140 169.120 32.200 169.400 ;
      RECT 0.140 171.360 32.200 171.640 ;
      RECT 0.140 173.600 32.200 173.880 ;
      RECT 0.140 175.840 32.200 176.120 ;
      RECT 0.140 178.080 32.200 178.360 ;
      RECT 0.140 180.320 32.200 180.600 ;
      RECT 0.140 182.560 32.200 182.840 ;
      RECT 0.140 184.800 32.200 185.080 ;
      RECT 0.140 187.040 32.200 187.320 ;
      RECT 0.140 189.280 32.200 189.560 ;
      RECT 0.140 191.520 32.200 191.800 ;
      RECT 0.140 193.760 32.200 194.040 ;
      RECT 0.140 196.000 32.200 196.280 ;
      RECT 0.140 198.240 32.200 198.520 ;
      RECT 0.140 200.480 32.200 200.760 ;
      RECT 0.140 202.720 32.200 203.000 ;
      RECT 0.140 204.960 32.200 205.240 ;
      RECT 0.140 207.200 32.200 207.480 ;
      RECT 0.140 209.440 32.200 209.720 ;
      RECT 0.140 211.680 32.200 211.960 ;
      RECT 0.140 213.920 32.200 214.200 ;
      RECT 0.140 216.160 32.200 216.440 ;
      RECT 0.140 218.400 32.200 218.680 ;
      RECT 0.140 220.640 32.200 220.920 ;
      RECT 0.140 222.880 32.200 223.160 ;
      RECT 0.140 225.120 32.200 225.400 ;
      RECT 0.140 227.360 32.200 227.640 ;
      RECT 0.140 229.600 32.200 229.880 ;
      RECT 0.140 231.840 32.200 232.120 ;
      RECT 0.140 234.080 32.200 234.360 ;
      RECT 0.140 236.320 32.200 236.600 ;
      RECT 0.140 238.560 32.200 238.840 ;
      RECT 0.140 240.800 32.200 241.080 ;
      RECT 0.140 243.040 32.200 243.320 ;
      RECT 0.140 245.280 32.200 245.560 ;
      RECT 0.140 247.520 32.200 247.800 ;
      RECT 0.140 249.760 32.200 250.040 ;
      RECT 0.140 252.000 32.200 252.280 ;
      RECT 0.140 254.240 32.200 254.520 ;
      RECT 0.140 256.480 32.200 256.760 ;
      RECT 0.140 258.720 32.200 259.000 ;
      RECT 0.140 260.960 32.200 261.240 ;
      RECT 0.140 263.200 32.200 263.480 ;
      RECT 0.140 265.440 32.200 265.720 ;
      RECT 0.140 267.680 32.200 267.960 ;
      RECT 0.140 269.920 32.200 270.200 ;
      RECT 0.140 272.160 32.200 272.440 ;
      RECT 0.140 274.400 32.200 274.680 ;
      RECT 0.140 276.640 32.200 276.920 ;
      RECT 0.140 278.880 32.200 279.160 ;
      RECT 0.140 281.120 32.200 281.400 ;
      RECT 0.140 283.360 32.200 283.640 ;
      RECT 0.140 285.600 32.200 285.880 ;
      RECT 0.140 287.840 32.200 288.120 ;
      RECT 0.140 290.080 32.200 290.360 ;
      RECT 0.140 292.320 32.200 292.600 ;
      RECT 0.140 294.560 32.200 294.840 ;
      RECT 0.140 296.800 32.200 297.080 ;
      RECT 0.140 299.040 32.200 299.320 ;
      RECT 0.140 301.280 32.200 301.560 ;
      RECT 0.140 303.520 32.200 303.800 ;
      RECT 0.140 305.760 32.200 306.040 ;
      RECT 0.140 308.000 32.200 308.280 ;
      RECT 0.140 310.240 32.200 310.520 ;
      RECT 0.140 312.480 32.200 312.760 ;
      RECT 0.140 314.720 32.200 315.000 ;
      RECT 0.140 316.960 32.200 317.240 ;
      RECT 0.140 319.200 32.200 319.480 ;
      RECT 0.140 321.440 32.200 321.720 ;
      RECT 0.140 323.680 32.200 323.960 ;
      RECT 0.140 325.920 32.200 326.200 ;
      RECT 0.140 328.160 32.200 328.440 ;
      RECT 0.140 330.400 32.200 330.680 ;
      RECT 0.140 332.640 32.200 332.920 ;
      RECT 0.140 334.880 32.200 335.160 ;
      RECT 0.140 337.120 32.200 337.400 ;
      RECT 0.140 339.360 32.200 339.640 ;
      RECT 0.140 341.600 32.200 341.880 ;
      RECT 0.140 343.840 32.200 344.120 ;
      RECT 0.140 346.080 32.200 346.360 ;
      RECT 0.140 348.320 32.200 348.600 ;
      RECT 0.140 350.560 32.200 350.840 ;
      RECT 0.140 352.800 32.200 353.080 ;
      RECT 0.140 355.040 32.200 355.320 ;
      RECT 0.140 357.280 32.200 357.560 ;
      RECT 0.140 359.520 32.200 359.800 ;
      RECT 0.140 361.760 32.200 362.040 ;
      RECT 0.140 364.000 32.200 364.280 ;
      RECT 0.140 366.240 32.200 366.520 ;
      RECT 0.140 368.480 32.200 368.760 ;
      RECT 0.140 370.720 32.200 371.000 ;
      RECT 0.140 372.960 32.200 373.240 ;
      RECT 0.140 375.200 32.200 375.480 ;
      RECT 0.140 377.440 32.200 377.720 ;
      RECT 0.140 379.680 32.200 379.960 ;
      RECT 0.140 381.920 32.200 382.200 ;
      RECT 0.140 384.160 32.200 384.440 ;
      RECT 0.140 386.400 32.200 386.680 ;
      RECT 0.140 388.640 32.200 388.920 ;
      RECT 0.140 390.880 32.200 391.160 ;
      RECT 0.140 393.120 32.200 393.400 ;
      RECT 0.140 395.360 32.200 395.640 ;
      RECT 0.140 397.600 32.200 397.880 ;
      RECT 0.140 399.840 32.200 400.120 ;
      RECT 0.140 402.080 32.200 402.360 ;
      RECT 0.140 404.320 32.200 404.600 ;
      RECT 0.140 406.560 32.200 406.840 ;
      RECT 0.140 408.800 32.200 409.080 ;
      RECT 0.140 411.040 32.200 411.320 ;
      RECT 0.140 413.280 32.200 413.560 ;
      RECT 0.140 415.520 32.200 415.800 ;
      RECT 0.140 417.760 32.200 418.040 ;
      RECT 0.140 420.000 32.200 420.280 ;
      RECT 0.140 422.240 32.200 422.520 ;
      RECT 0.140 424.480 32.200 424.760 ;
      RECT 0.140 426.720 32.200 427.000 ;
      RECT 0.140 428.960 32.200 429.240 ;
      RECT 0.140 431.200 32.200 431.480 ;
      RECT 0.140 433.440 32.200 433.720 ;
      RECT 0.140 435.680 32.200 435.960 ;
      RECT 0.140 437.920 32.200 438.200 ;
      RECT 0.140 440.160 32.200 440.440 ;
      RECT 0.140 442.400 32.200 442.680 ;
      RECT 0.140 444.640 32.200 444.920 ;
      RECT 0.140 446.880 32.200 447.160 ;
      RECT 0.140 449.120 32.200 449.400 ;
      RECT 0.140 451.360 32.200 451.640 ;
      RECT 0.140 453.600 32.200 453.880 ;
      RECT 0.140 455.840 32.200 456.120 ;
      RECT 0.140 458.080 32.200 458.360 ;
      RECT 0.140 460.320 32.200 460.600 ;
      RECT 0.140 462.560 32.200 462.840 ;
      RECT 0.140 464.800 32.200 465.080 ;
      RECT 0.140 467.040 32.200 467.320 ;
      RECT 0.140 469.280 32.200 469.560 ;
      RECT 0.140 471.520 32.200 471.800 ;
      RECT 0.140 473.760 32.200 474.040 ;
      RECT 0.140 476.000 32.200 476.280 ;
      RECT 0.140 478.240 32.200 478.520 ;
      RECT 0.140 480.480 32.200 480.760 ;
      RECT 0.140 482.720 32.200 483.000 ;
      RECT 0.140 484.960 32.200 485.240 ;
      RECT 0.140 487.200 32.200 487.480 ;
      RECT 0.140 489.440 32.200 489.720 ;
      RECT 0.140 491.680 32.200 491.960 ;
      RECT 0.140 493.920 32.200 494.200 ;
      RECT 0.140 496.160 32.200 496.440 ;
      RECT 0.140 498.400 32.200 498.680 ;
      RECT 0.140 500.640 32.200 500.920 ;
      RECT 0.140 502.880 32.200 503.160 ;
      RECT 0.140 505.120 32.200 505.400 ;
      RECT 0.140 507.360 32.200 507.640 ;
      RECT 0.140 509.600 32.200 509.880 ;
      RECT 0.140 511.840 32.200 512.120 ;
      RECT 0.140 514.080 32.200 514.360 ;
      RECT 0.140 516.320 32.200 516.600 ;
      RECT 0.140 518.560 32.200 518.840 ;
      RECT 0.140 520.800 32.200 521.080 ;
      RECT 0.140 523.040 32.200 523.320 ;
      RECT 0.140 525.280 32.200 525.560 ;
      RECT 0.140 527.520 32.200 527.800 ;
      RECT 0.140 529.760 32.200 530.040 ;
      RECT 0.140 532.000 32.200 532.280 ;
      RECT 0.140 534.240 32.200 534.520 ;
      RECT 0.140 536.480 32.200 536.760 ;
      RECT 0.140 538.720 32.200 539.000 ;
      RECT 0.140 540.960 32.200 541.240 ;
      RECT 0.140 543.200 32.200 543.480 ;
      RECT 0.140 545.440 32.200 545.720 ;
      RECT 0.140 547.680 32.200 547.960 ;
      RECT 0.140 549.920 32.200 550.200 ;
      RECT 0.140 552.160 32.200 552.440 ;
      RECT 0.140 554.400 32.200 554.680 ;
      RECT 0.140 556.640 32.200 556.920 ;
      RECT 0.140 558.880 32.200 559.160 ;
      RECT 0.140 561.120 32.200 561.400 ;
      RECT 0.140 563.360 32.200 563.640 ;
      RECT 0.140 565.600 32.200 565.880 ;
      RECT 0.140 567.840 32.200 568.120 ;
      RECT 0.140 570.080 32.200 570.360 ;
      RECT 0.140 572.320 32.200 572.600 ;
      RECT 0.140 574.560 32.200 574.840 ;
      RECT 0.140 576.800 32.200 577.080 ;
      RECT 0.140 579.040 32.200 579.320 ;
      RECT 0.140 581.280 32.200 581.560 ;
      RECT 0.140 583.520 32.200 583.800 ;
      RECT 0.140 585.760 32.200 586.040 ;
      RECT 0.140 588.000 32.200 588.280 ;
      RECT 0.140 590.240 32.200 590.520 ;
      RECT 0.140 592.480 32.200 592.760 ;
      RECT 0.140 594.720 32.200 595.000 ;
      RECT 0.140 596.960 32.200 597.240 ;
      RECT 0.140 599.200 32.200 599.480 ;
      RECT 0.140 601.440 32.200 601.720 ;
      RECT 0.140 603.680 32.200 603.960 ;
      RECT 0.140 605.920 32.200 606.200 ;
      RECT 0.140 608.160 32.200 608.440 ;
      RECT 0.140 610.400 32.200 610.680 ;
      RECT 0.140 612.640 32.200 612.920 ;
      RECT 0.140 614.880 32.200 615.160 ;
      RECT 0.140 617.120 32.200 617.400 ;
      RECT 0.140 619.360 32.200 619.640 ;
      RECT 0.140 621.600 32.200 621.880 ;
      RECT 0.140 623.840 32.200 624.120 ;
      RECT 0.140 626.080 32.200 626.360 ;
      RECT 0.140 628.320 32.200 628.600 ;
      RECT 0.140 630.560 32.200 630.840 ;
      RECT 0.140 632.800 32.200 633.080 ;
      RECT 0.140 635.040 32.200 635.320 ;
      RECT 0.140 637.280 32.200 637.560 ;
      RECT 0.140 639.520 32.200 639.800 ;
      RECT 0.140 641.760 32.200 642.040 ;
      RECT 0.140 644.000 32.200 644.280 ;
    END
  END VDD
  OBS
    LAYER metal1 ;
    RECT 0 0 32.340 645.400 ;
    LAYER metal2 ;
    RECT 0 0 32.340 645.400 ;
  END
END fakeram_64x256
END LIBRARY
